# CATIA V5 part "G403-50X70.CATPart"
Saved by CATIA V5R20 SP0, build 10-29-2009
Part number: G403-50X70
Definition: NONE
Nomenclature: G403-50X70
Source: Unknown
Description: G403-50X70
Bounding box of the stored display mesh (mm): x -33 to 37, y -40 to 40, z -40 to 40
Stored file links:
  C:\Users\Utente\Desktop\IO LAVORO\3D X SITO CF\X SITO\PLASTICA\G403\G403-50X70.CATPart

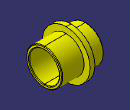
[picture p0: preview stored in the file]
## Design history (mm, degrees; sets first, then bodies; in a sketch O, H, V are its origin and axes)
Body1 "G403-50X70" (main body)
  Solid1: solid without history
